VERSION 5.7 ;
  NOWIREEXTENSIONATPIN ON ;
  DIVIDERCHAR "/" ;
  BUSBITCHARS "[]" ;
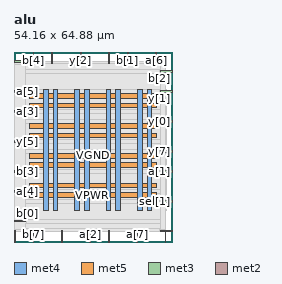
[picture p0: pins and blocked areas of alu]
MACRO alu
  CLASS BLOCK ;
  FOREIGN alu ;
  ORIGIN 0.000 0.000 ;
  SIZE 54.160 BY 64.880 ;
  PIN VGND
    DIRECTION INOUT ;
    USE GROUND ;
    PORT
      LAYER met4 ;
        RECT 13.365 10.640 14.965 51.920 ;
    END
    PORT
      LAYER met4 ;
        RECT 24.060 10.640 25.660 51.920 ;
    END
    PORT
      LAYER met4 ;
        RECT 34.755 10.640 36.355 51.920 ;
    END
    PORT
      LAYER met4 ;
        RECT 45.450 10.640 47.050 51.920 ;
    END
    PORT
      LAYER met5 ;
        RECT 5.280 18.480 48.540 20.080 ;
    END
    PORT
      LAYER met5 ;
        RECT 5.280 28.680 48.540 30.280 ;
    END
    PORT
      LAYER met5 ;
        RECT 5.280 38.880 48.540 40.480 ;
    END
    PORT
      LAYER met5 ;
        RECT 5.280 49.080 48.540 50.680 ;
    END
  END VGND
  PIN VPWR
    DIRECTION INOUT ;
    USE POWER ;
    PORT
      LAYER met4 ;
        RECT 10.065 10.640 11.665 51.920 ;
    END
    PORT
      LAYER met4 ;
        RECT 20.760 10.640 22.360 51.920 ;
    END
    PORT
      LAYER met4 ;
        RECT 31.455 10.640 33.055 51.920 ;
    END
    PORT
      LAYER met4 ;
        RECT 42.150 10.640 43.750 51.920 ;
    END
    PORT
      LAYER met5 ;
        RECT 5.280 15.180 48.540 16.780 ;
    END
    PORT
      LAYER met5 ;
        RECT 5.280 25.380 48.540 26.980 ;
    END
    PORT
      LAYER met5 ;
        RECT 5.280 35.580 48.540 37.180 ;
    END
    PORT
      LAYER met5 ;
        RECT 5.280 45.780 48.540 47.380 ;
    END
  END VPWR
  PIN a[0]
    DIRECTION INPUT ;
    USE SIGNAL ;
    ANTENNAGATEAREA 0.126000 ;
    PORT
      LAYER met3 ;
        RECT 50.160 3.440 54.160 4.040 ;
    END
  END a[0]
  PIN a[1]
    DIRECTION INPUT ;
    USE SIGNAL ;
    ANTENNAGATEAREA 0.213000 ;
    PORT
      LAYER met3 ;
        RECT 50.160 23.840 54.160 24.440 ;
    END
  END a[1]
  PIN a[2]
    DIRECTION INPUT ;
    USE SIGNAL ;
    ANTENNAGATEAREA 0.159000 ;
    PORT
      LAYER met2 ;
        RECT 25.850 0.000 26.130 4.000 ;
    END
  END a[2]
  PIN a[3]
    DIRECTION INPUT ;
    USE SIGNAL ;
    ANTENNAGATEAREA 0.213000 ;
    PORT
      LAYER met3 ;
        RECT 0.000 44.240 4.000 44.840 ;
    END
  END a[3]
  PIN a[4]
    DIRECTION INPUT ;
    USE SIGNAL ;
    ANTENNAGATEAREA 0.159000 ;
    PORT
      LAYER met3 ;
        RECT 0.000 17.040 4.000 17.640 ;
    END
  END a[4]
  PIN a[5]
    DIRECTION INPUT ;
    USE SIGNAL ;
    ANTENNAGATEAREA 0.213000 ;
    PORT
      LAYER met3 ;
        RECT 0.000 51.040 4.000 51.640 ;
    END
  END a[5]
  PIN a[6]
    DIRECTION INPUT ;
    USE SIGNAL ;
    ANTENNAGATEAREA 0.213000 ;
    PORT
      LAYER met2 ;
        RECT 48.390 60.880 48.670 64.880 ;
    END
  END a[6]
  PIN a[7]
    DIRECTION INPUT ;
    USE SIGNAL ;
    ANTENNAGATEAREA 0.196500 ;
    PORT
      LAYER met2 ;
        RECT 41.950 0.000 42.230 4.000 ;
    END
  END a[7]
  PIN b[0]
    DIRECTION INPUT ;
    USE SIGNAL ;
    ANTENNAGATEAREA 0.213000 ;
    PORT
      LAYER met3 ;
        RECT 0.000 6.840 4.000 7.440 ;
    END
  END b[0]
  PIN b[1]
    DIRECTION INPUT ;
    USE SIGNAL ;
    ANTENNAGATEAREA 0.126000 ;
    PORT
      LAYER met2 ;
        RECT 38.730 60.880 39.010 64.880 ;
    END
  END b[1]
  PIN b[2]
    DIRECTION INPUT ;
    USE SIGNAL ;
    ANTENNAGATEAREA 0.159000 ;
    PORT
      LAYER met3 ;
        RECT 50.160 57.840 54.160 58.440 ;
    END
  END b[2]
  PIN b[3]
    DIRECTION INPUT ;
    USE SIGNAL ;
    ANTENNAGATEAREA 0.213000 ;
    PORT
      LAYER met3 ;
        RECT 0.000 23.840 4.000 24.440 ;
    END
  END b[3]
  PIN b[4]
    DIRECTION INPUT ;
    USE SIGNAL ;
    ANTENNAGATEAREA 0.213000 ;
    PORT
      LAYER met2 ;
        RECT 6.530 60.880 6.810 64.880 ;
    END
  END b[4]
  PIN b[5]
    DIRECTION INPUT ;
    USE SIGNAL ;
    ANTENNAGATEAREA 0.213000 ;
    PORT
      LAYER met2 ;
        RECT 51.610 0.000 51.890 4.000 ;
    END
  END b[5]
  PIN b[6]
    DIRECTION INPUT ;
    USE SIGNAL ;
    ANTENNAGATEAREA 0.213000 ;
    PORT
      LAYER met2 ;
        RECT 0.090 0.000 0.370 4.000 ;
    END
  END b[6]
  PIN b[7]
    DIRECTION INPUT ;
    USE SIGNAL ;
    ANTENNAGATEAREA 0.196500 ;
    PORT
      LAYER met2 ;
        RECT 6.530 0.000 6.810 4.000 ;
    END
  END b[7]
  PIN sel[0]
    DIRECTION INPUT ;
    USE SIGNAL ;
    ANTENNAGATEAREA 0.213000 ;
    PORT
      LAYER met2 ;
        RECT 12.970 60.880 13.250 64.880 ;
    END
  END sel[0]
  PIN sel[1]
    DIRECTION INPUT ;
    USE SIGNAL ;
    ANTENNAGATEAREA 0.213000 ;
    PORT
      LAYER met3 ;
        RECT 50.160 13.640 54.160 14.240 ;
    END
  END sel[1]
  PIN sel[2]
    DIRECTION INPUT ;
    USE SIGNAL ;
    ANTENNAGATEAREA 0.213000 ;
    PORT
      LAYER met2 ;
        RECT 16.190 0.000 16.470 4.000 ;
    END
  END sel[2]
  PIN y[0]
    DIRECTION OUTPUT TRISTATE ;
    USE SIGNAL ;
    ANTENNADIFFAREA 0.795200 ;
    PORT
      LAYER met3 ;
        RECT 50.160 40.840 54.160 41.440 ;
    END
  END y[0]
  PIN y[1]
    DIRECTION OUTPUT TRISTATE ;
    USE SIGNAL ;
    ANTENNADIFFAREA 0.795200 ;
    PORT
      LAYER met3 ;
        RECT 50.160 51.040 54.160 51.640 ;
    END
  END y[1]
  PIN y[2]
    DIRECTION OUTPUT TRISTATE ;
    USE SIGNAL ;
    ANTENNADIFFAREA 0.795200 ;
    PORT
      LAYER met2 ;
        RECT 22.630 60.880 22.910 64.880 ;
    END
  END y[2]
  PIN y[3]
    DIRECTION OUTPUT TRISTATE ;
    USE SIGNAL ;
    ANTENNADIFFAREA 0.795200 ;
    PORT
      LAYER met2 ;
        RECT 32.290 60.880 32.570 64.880 ;
    END
  END y[3]
  PIN y[4]
    DIRECTION OUTPUT TRISTATE ;
    USE SIGNAL ;
    ANTENNADIFFAREA 0.795200 ;
    PORT
      LAYER met2 ;
        RECT 32.290 0.000 32.570 4.000 ;
    END
  END y[4]
  PIN y[5]
    DIRECTION OUTPUT TRISTATE ;
    USE SIGNAL ;
    ANTENNADIFFAREA 0.795200 ;
    PORT
      LAYER met3 ;
        RECT 0.000 34.040 4.000 34.640 ;
    END
  END y[5]
  PIN y[6]
    DIRECTION OUTPUT TRISTATE ;
    USE SIGNAL ;
    ANTENNADIFFAREA 0.795200 ;
    PORT
      LAYER met3 ;
        RECT 0.000 61.240 4.000 61.840 ;
    END
  END y[6]
  PIN y[7]
    DIRECTION OUTPUT TRISTATE ;
    USE SIGNAL ;
    ANTENNADIFFAREA 0.445500 ;
    PORT
      LAYER met3 ;
        RECT 50.160 30.640 54.160 31.240 ;
    END
  END y[7]
  OBS
      LAYER li1 ;
        RECT 5.520 10.795 48.300 51.765 ;
      LAYER met1 ;
        RECT 0.070 10.640 51.910 51.920 ;
      LAYER met2 ;
        RECT 0.100 60.600 6.250 61.610 ;
        RECT 7.090 60.600 12.690 61.610 ;
        RECT 13.530 60.600 22.350 61.610 ;
        RECT 23.190 60.600 32.010 61.610 ;
        RECT 32.850 60.600 38.450 61.610 ;
        RECT 39.290 60.600 48.110 61.610 ;
        RECT 48.950 60.600 51.880 61.610 ;
        RECT 0.100 4.280 51.880 60.600 ;
        RECT 0.650 3.555 6.250 4.280 ;
        RECT 7.090 3.555 15.910 4.280 ;
        RECT 16.750 3.555 25.570 4.280 ;
        RECT 26.410 3.555 32.010 4.280 ;
        RECT 32.850 3.555 41.670 4.280 ;
        RECT 42.510 3.555 51.330 4.280 ;
      LAYER met3 ;
        RECT 4.400 60.840 50.160 61.690 ;
        RECT 4.000 58.840 50.160 60.840 ;
        RECT 4.000 57.440 49.760 58.840 ;
        RECT 4.000 52.040 50.160 57.440 ;
        RECT 4.400 50.640 49.760 52.040 ;
        RECT 4.000 45.240 50.160 50.640 ;
        RECT 4.400 43.840 50.160 45.240 ;
        RECT 4.000 41.840 50.160 43.840 ;
        RECT 4.000 40.440 49.760 41.840 ;
        RECT 4.000 35.040 50.160 40.440 ;
        RECT 4.400 33.640 50.160 35.040 ;
        RECT 4.000 31.640 50.160 33.640 ;
        RECT 4.000 30.240 49.760 31.640 ;
        RECT 4.000 24.840 50.160 30.240 ;
        RECT 4.400 23.440 49.760 24.840 ;
        RECT 4.000 18.040 50.160 23.440 ;
        RECT 4.400 16.640 50.160 18.040 ;
        RECT 4.000 14.640 50.160 16.640 ;
        RECT 4.000 13.240 49.760 14.640 ;
        RECT 4.000 7.840 50.160 13.240 ;
        RECT 4.400 6.440 50.160 7.840 ;
        RECT 4.000 4.440 50.160 6.440 ;
        RECT 4.000 3.575 49.760 4.440 ;
  END
END alu
END LIBRARY

